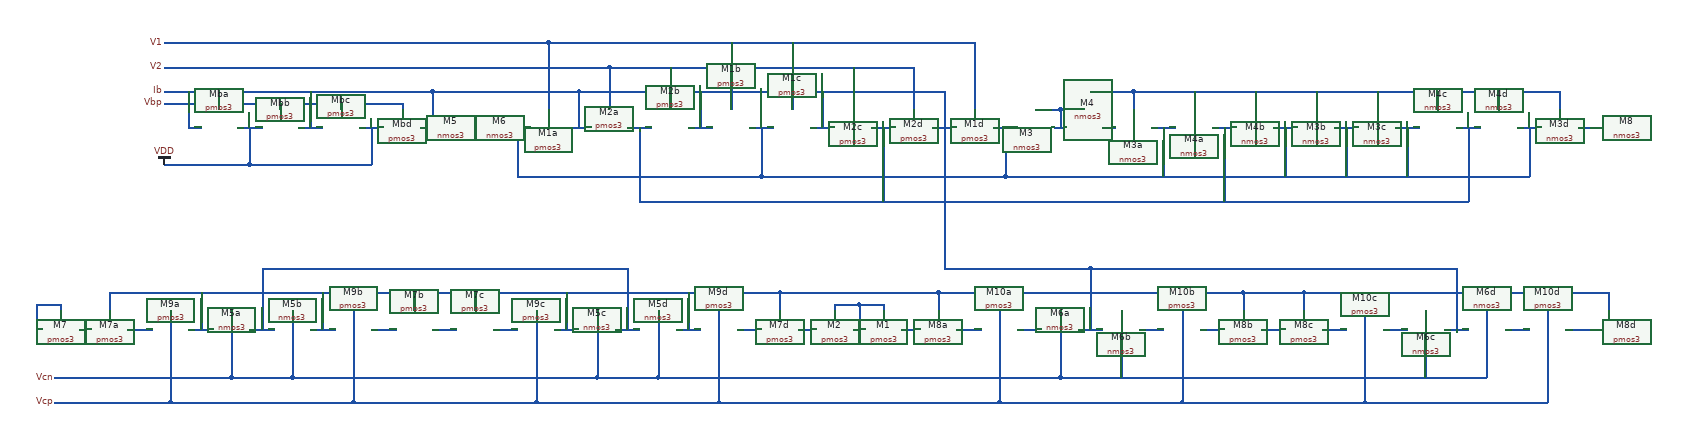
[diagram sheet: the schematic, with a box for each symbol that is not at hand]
v {xschem version=2.9.9 file_version=1.2 }
G {}
K {}
V {}
S {}
E {}
N 1240 -550 1280 -550 { lab=VDD}
N 1340 -550 1380 -550 { lab=Ib}
N 1440 -550 1480 -550 { lab=VDD}
N 1210 -590 1510 -590 { lab=Ib}
N 1510 -590 1510 -580 { lab=Ib}
N 1210 -590 1210 -580 { lab=Ib}
N 1160 -590 1210 -590 { lab=Ib}
N 1160 -550 1180 -550 { lab=Ib}
N 1780 -550 1820 -550 { lab=Ib}
N 1800 -610 1800 -550 { lab=Ib}
N 1800 -610 2400 -610 { lab=Ib}
N 2400 -610 2400 -550 { lab=Ib}
N 2380 -550 2420 -550 { lab=Ib}
N 1980 -550 2020 -550 { lab=Ib}
N 2000 -610 2000 -550 { lab=Ib}
N 2180 -550 2220 -550 { lab=Ib}
N 2200 -610 2200 -550 { lab=Ib}
N 1850 -650 1850 -580 { lab=V2}
N 1950 -650 1950 -580 { lab=V2}
N 2250 -650 2250 -580 { lab=V2}
N 2350 -650 2350 -580 { lab=V2}
N 1850 -650 2350 -650 { lab=V2}
N 1750 -690 1750 -580 { lab=V1}
N 1750 -690 2440 -690 { lab=V1}
N 2440 -690 2450 -690 { lab=V1}
N 2450 -690 2450 -580 { lab=V1}
N 2050 -690 2050 -580 { lab=V1}
N 2150 -690 2150 -580 { lab=V1}
N 1720 -650 1850 -650 { lab=V2}
N 1720 -690 1750 -690 { lab=V1}
N 2090 -550 2120 -550 { lab=#net1}
N 2080 -550 2090 -550 { lab=#net1}
N 2100 -550 2100 -470 { lab=#net1}
N 1700 -550 1700 -470 { lab=#net1}
N 1700 -470 2100 -470 { lab=#net1}
N 2100 -470 2500 -470 { lab=#net1}
N 2500 -550 2500 -470 { lab=#net1}
N 2480 -550 2500 -550 { lab=#net1}
N 1700 -550 1720 -550 { lab=#net1}
N 1700 -690 1720 -690 { lab=V1}
N 1700 -650 1720 -650 { lab=V2}
N 1880 -550 1920 -550 { lab=#net2}
N 1900 -550 1900 -450 { lab=#net2}
N 1900 -450 1900 -430 { lab=#net2}
N 1900 -430 2560 -430 { lab=#net2}
N 2500 -470 2560 -470 { lab=#net1}
N 2280 -550 2320 -550 { lab=#net2}
N 2300 -550 2300 -430 { lab=#net2}
N 2740 -550 2780 -550 { lab=#net1}
N 2840 -550 2880 -550 { lab=#net2}
N 2940 -550 2980 -550 { lab=#net1}
N 3040 -550 3080 -550 { lab=#net1}
N 3140 -550 3180 -550 { lab=#net1}
N 3240 -550 3280 -550 { lab=#net2}
N 3340 -550 3380 -550 { lab=#net1}
N 2710 -610 3410 -610 { lab=#net3}
N 3410 -610 3410 -580 { lab=#net3}
N 3310 -610 3310 -580 { lab=#net3}
N 3210 -610 3210 -580 { lab=#net3}
N 3110 -610 3110 -580 { lab=#net3}
N 3010 -610 3010 -580 { lab=#net3}
N 2910 -610 2910 -580 { lab=#net3}
N 2810 -610 2810 -580 { lab=#net3}
N 2710 -610 2710 -580 { lab=#net3}
N 2660 -610 2710 -610 { lab=#net3}
N 3440 -550 3460 -550 { lab=#net4}
N 2660 -550 2680 -550 { lab=#net5}
N 3060 -550 3060 -470 { lab=#net1}
N 2640 -610 2660 -610 { lab=#net3}
N 1030 -280 1030 -250 { lab=#net6}
N 1030 -280 1930 -280 { lab=#net6}
N 1930 -280 2130 -280 { lab=#net6}
N 2130 -280 2130 -250 { lab=#net6}
N 1530 -280 1530 -250 { lab=#net6}
N 1630 -280 1630 -250 { lab=#net6}
N 1380 -280 1380 -220 { lab=#net6}
N 1180 -280 1180 -220 { lab=#net6}
N 1780 -280 1780 -220 { lab=#net6}
N 1980 -280 1980 -220 { lab=#net6}
N 1160 -220 1200 -220 { lab=#net6}
N 1360 -220 1400 -220 { lab=#net6}
N 1460 -220 1500 -220 { lab=#net7}
N 1560 -220 1600 -220 { lab=#net8}
N 1660 -220 1700 -220 { lab=#net9}
N 1760 -220 1800 -220 { lab=#net6}
N 1860 -220 1900 -220 { lab=#net10}
N 1960 -220 2000 -220 { lab=#net6}
N 2060 -220 2100 -220 { lab=#net11}
N 1280 -320 1280 -220 { lab=#net10}
N 1280 -320 1880 -320 { lab=#net10}
N 1880 -320 1880 -220 { lab=#net10}
N 1260 -220 1300 -220 { lab=#net10}
N 1060 -220 1100 -220 { lab=#net12}
N 1330 -250 1330 -140 { lab=Vcn}
N 1230 -250 1230 -140 { lab=Vcn}
N 1830 -250 1830 -140 { lab=Vcn}
N 1930 -250 1930 -140 { lab=Vcn}
N 1830 -140 1930 -140 { lab=Vcn}
N 1330 -140 1830 -140 { lab=Vcn}
N 1230 -140 1330 -140 { lab=Vcn}
N 940 -140 1230 -140 { lab=Vcn}
N 1130 -250 1130 -100 { lab=Vcp}
N 1130 -100 1430 -100 { lab=Vcp}
N 1430 -250 1430 -100 { lab=Vcp}
N 1430 -100 1730 -100 { lab=Vcp}
N 1730 -250 1730 -100 { lab=Vcp}
N 1730 -100 2030 -100 { lab=Vcp}
N 2030 -250 2030 -100 { lab=Vcp}
N 940 -100 1130 -100 { lab=Vcp}
N 2420 -220 2460 -220 { lab=#net13}
N 2530 -220 2560 -220 { lab=#net14}
N 2520 -220 2530 -220 { lab=#net14}
N 2620 -220 2660 -220 { lab=Ib}
N 2720 -220 2760 -220 { lab=#net15}
N 2820 -220 2860 -220 { lab=#net16}
N 2920 -220 2960 -220 { lab=#net17}
N 3020 -220 3060 -220 { lab=#net18}
N 3120 -220 3160 -220 { lab=#net19}
N 3220 -220 3260 -220 { lab=Ib}
N 3320 -220 3360 -220 { lab=#net20}
N 3420 -220 3460 -220 { lab=#net21}
N 2640 -320 2640 -220 { lab=Ib}
N 2640 -320 3240 -320 { lab=Ib}
N 3240 -320 3240 -220 { lab=Ib}
N 1990 -140 2320 -140 { lab=Vcn}
N 2590 -250 2590 -140 { lab=Vcn}
N 2320 -140 2590 -140 { lab=Vcn}
N 2690 -250 2690 -140 { lab=Vcn}
N 3190 -250 3190 -140 { lab=Vcn}
N 3290 -250 3290 -140 { lab=Vcn}
N 2590 -140 3290 -140 { lab=Vcn}
N 2400 -320 2640 -320 { lab=Ib}
N 2400 -550 2400 -320 { lab=Ib}
N 2760 -550 2760 -470 { lab=#net1}
N 2960 -550 2960 -470 { lab=#net1}
N 3160 -550 3160 -470 { lab=#net1}
N 3360 -550 3360 -470 { lab=#net1}
N 2560 -470 2700 -470 { lab=#net1}
N 2860 -550 2860 -430 { lab=#net2}
N 3260 -550 3260 -430 { lab=#net2}
N 2090 -100 2490 -100 { lab=Vcp}
N 2490 -250 2490 -100 { lab=Vcp}
N 2790 -250 2790 -100 { lab=Vcp}
N 2490 -100 2790 -100 { lab=Vcp}
N 3090 -240 3090 -100 { lab=Vcp}
N 2790 -100 3090 -100 { lab=Vcp}
N 3390 -250 3390 -100 { lab=Vcp}
N 3090 -100 3390 -100 { lab=Vcp}
N 2260 -220 2270 -220 { lab=#net22}
N 2160 -220 2190 -220 { lab=#net23}
N 2330 -220 2360 -220 { lab=#net24}
N 2250 -220 2260 -220 { lab=#net22}
N 2220 -260 2220 -250 { lab=#net22}
N 2220 -260 2260 -260 { lab=#net22}
N 2260 -260 2260 -220 { lab=#net22}
N 2260 -260 2300 -260 { lab=#net22}
N 2300 -260 2300 -250 { lab=#net22}
N 1930 -140 1990 -140 { lab=Vcn}
N 2030 -100 2090 -100 { lab=Vcp}
N 2130 -280 2390 -280 { lab=#net6}
N 2390 -280 2390 -250 { lab=#net6}
N 2390 -280 2890 -280 { lab=#net6}
N 2890 -280 2890 -250 { lab=#net6}
N 2890 -280 2990 -280 { lab=#net6}
N 2990 -280 2990 -250 { lab=#net6}
N 2990 -280 3490 -280 { lab=#net6}
N 3490 -280 3490 -250 { lab=#net6}
N 1310 -590 1310 -580 { lab=Ib}
N 1410 -590 1410 -580 { lab=Ib}
N 1540 -550 1560 -550 { lab=Ib}
N 1560 -610 1560 -550 { lab=Ib}
N 1560 -610 1800 -610 { lab=Ib}
N 1260 -550 1260 -490 { lab=VDD}
N 1460 -550 1460 -490 { lab=VDD}
N 1260 -490 1460 -490 { lab=VDD}
N 1120 -490 1260 -490 { lab=VDD}
N 1120 -590 1160 -590 { lab=Vbp}
N 1160 -610 1160 -550 { lab=Ib}
N 1360 -610 1360 -550 { lab=Ib}
N 1120 -650 1700 -650 { lab=V2}
N 1120 -690 1700 -690 { lab=V1}
N 1120 -610 1560 -610 { lab=Ib}
N 980 -220 1000 -220 { lab=#net25}
N 910 -250 910 -220 { lab=#net26}
N 910 -260 910 -250 { lab=#net26}
N 910 -260 950 -260 { lab=#net26}
N 950 -260 950 -250 { lab=#net26}
N 910 -220 920 -220 { lab=#net26}
N 2700 -470 3350 -470 { lab=#net1}
N 3350 -470 3360 -470 { lab=#net1}
N 2560 -430 3260 -430 { lab=#net2}
N 2500 -550 2520 -550 { lab=#net1}
N 2580 -550 2600 -550 { lab=#net27}
N 2550 -580 2590 -580 { lab=#net27}
N 2590 -580 2590 -550 { lab=#net27}
N 2590 -580 2630 -580 { lab=#net27}
C {madvlsi/nmos3.sym} 2710 -550 1 0 {name=M3a
L=0.5
W=3
body=GND
nf=1
mult=1
ad="'int((nf+1)/2) * W/nf * 0.29'" 
pd="'2*int((nf+1)/2) * (W/nf + 0.29)'"
as="'int((nf+2)/2) * W/nf * 0.29'" 
ps="'2*int((nf+2)/2) * (W/nf + 0.29)'"
nrd="'0.29 / W'" nrs="'0.29 / W'"
sa=0 sb=0 sd=0
model=nfet_01v8
spiceprefix=X
}
C {madvlsi/nmos3.sym} 2810 -550 1 0 {name=M4a
L=0.5
W=3
body=GND
nf=1
mult=1
ad="'int((nf+1)/2) * W/nf * 0.29'" 
pd="'2*int((nf+1)/2) * (W/nf + 0.29)'"
as="'int((nf+2)/2) * W/nf * 0.29'" 
ps="'2*int((nf+2)/2) * (W/nf + 0.29)'"
nrd="'0.29 / W'" nrs="'0.29 / W'"
sa=0 sb=0 sd=0
model=nfet_01v8
spiceprefix=X
}
C {madvlsi/nmos3.sym} 2910 -550 1 0 {name=M4b
L=0.5
W=3
body=GND
nf=1
mult=1
ad="'int((nf+1)/2) * W/nf * 0.29'" 
pd="'2*int((nf+1)/2) * (W/nf + 0.29)'"
as="'int((nf+2)/2) * W/nf * 0.29'" 
ps="'2*int((nf+2)/2) * (W/nf + 0.29)'"
nrd="'0.29 / W'" nrs="'0.29 / W'"
sa=0 sb=0 sd=0
model=nfet_01v8
spiceprefix=X
}
C {madvlsi/nmos3.sym} 3010 -550 1 0 {name=M3b
L=0.5
W=3
body=GND
nf=1
mult=1
ad="'int((nf+1)/2) * W/nf * 0.29'" 
pd="'2*int((nf+1)/2) * (W/nf + 0.29)'"
as="'int((nf+2)/2) * W/nf * 0.29'" 
ps="'2*int((nf+2)/2) * (W/nf + 0.29)'"
nrd="'0.29 / W'" nrs="'0.29 / W'"
sa=0 sb=0 sd=0
model=nfet_01v8
spiceprefix=X
}
C {madvlsi/nmos3.sym} 3110 -550 1 0 {name=M3c
L=0.5
W=3
body=GND
nf=1
mult=1
ad="'int((nf+1)/2) * W/nf * 0.29'" 
pd="'2*int((nf+1)/2) * (W/nf + 0.29)'"
as="'int((nf+2)/2) * W/nf * 0.29'" 
ps="'2*int((nf+2)/2) * (W/nf + 0.29)'"
nrd="'0.29 / W'" nrs="'0.29 / W'"
sa=0 sb=0 sd=0
model=nfet_01v8
spiceprefix=X
}
C {madvlsi/nmos3.sym} 3210 -550 1 0 {name=M4c
L=0.5
W=3
body=GND
nf=1
mult=1
ad="'int((nf+1)/2) * W/nf * 0.29'" 
pd="'2*int((nf+1)/2) * (W/nf + 0.29)'"
as="'int((nf+2)/2) * W/nf * 0.29'" 
ps="'2*int((nf+2)/2) * (W/nf + 0.29)'"
nrd="'0.29 / W'" nrs="'0.29 / W'"
sa=0 sb=0 sd=0
model=nfet_01v8
spiceprefix=X
}
C {madvlsi/nmos3.sym} 3310 -550 1 0 {name=M4d
L=0.5
W=3
body=GND
nf=1
mult=1
ad="'int((nf+1)/2) * W/nf * 0.29'" 
pd="'2*int((nf+1)/2) * (W/nf + 0.29)'"
as="'int((nf+2)/2) * W/nf * 0.29'" 
ps="'2*int((nf+2)/2) * (W/nf + 0.29)'"
nrd="'0.29 / W'" nrs="'0.29 / W'"
sa=0 sb=0 sd=0
model=nfet_01v8
spiceprefix=X
}
C {madvlsi/nmos3.sym} 3410 -550 1 0 {name=M3d
L=0.5
W=3
body=GND
nf=1
mult=1
ad="'int((nf+1)/2) * W/nf * 0.29'" 
pd="'2*int((nf+1)/2) * (W/nf + 0.29)'"
as="'int((nf+2)/2) * W/nf * 0.29'" 
ps="'2*int((nf+2)/2) * (W/nf + 0.29)'"
nrd="'0.29 / W'" nrs="'0.29 / W'"
sa=0 sb=0 sd=0
model=nfet_01v8
spiceprefix=X
}
C {madvlsi/pmos3.sym} 1210 -550 1 0 {name=Mba
L=0.5
W=3
body=VDD
nf=1
mult=1
ad="'int((nf+1)/2) * W/nf * 0.29'" 
pd="'2*int((nf+1)/2) * (W/nf + 0.29)'"
as="'int((nf+2)/2) * W/nf * 0.29'" 
ps="'2*int((nf+2)/2) * (W/nf + 0.29)'"
nrd="'0.29 / W'" nrs="'0.29 / W'"
sa=0 sb=0 sd=0
model=pfet_01v8
spiceprefix=X
}
C {madvlsi/pmos3.sym} 1310 -550 1 0 {name=Mbb
L=0.5
W=3
body=VDD
nf=1
mult=1
ad="'int((nf+1)/2) * W/nf * 0.29'" 
pd="'2*int((nf+1)/2) * (W/nf + 0.29)'"
as="'int((nf+2)/2) * W/nf * 0.29'" 
ps="'2*int((nf+2)/2) * (W/nf + 0.29)'"
nrd="'0.29 / W'" nrs="'0.29 / W'"
sa=0 sb=0 sd=0
model=pfet_01v8
spiceprefix=X
}
C {madvlsi/pmos3.sym} 1410 -550 1 0 {name=Mbc
L=0.5
W=3
body=VDD
nf=1
mult=1
ad="'int((nf+1)/2) * W/nf * 0.29'" 
pd="'2*int((nf+1)/2) * (W/nf + 0.29)'"
as="'int((nf+2)/2) * W/nf * 0.29'" 
ps="'2*int((nf+2)/2) * (W/nf + 0.29)'"
nrd="'0.29 / W'" nrs="'0.29 / W'"
sa=0 sb=0 sd=0
model=pfet_01v8
spiceprefix=X
}
C {madvlsi/pmos3.sym} 1510 -550 1 0 {name=Mbd
L=0.5
W=3
body=VDD
nf=1
mult=1
ad="'int((nf+1)/2) * W/nf * 0.29'" 
pd="'2*int((nf+1)/2) * (W/nf + 0.29)'"
as="'int((nf+2)/2) * W/nf * 0.29'" 
ps="'2*int((nf+2)/2) * (W/nf + 0.29)'"
nrd="'0.29 / W'" nrs="'0.29 / W'"
sa=0 sb=0 sd=0
model=pfet_01v8
spiceprefix=X
}
C {madvlsi/pmos3.sym} 1750 -550 1 0 {name=M1a
L=0.5
W=3
body=VDD
nf=1
mult=1
ad="'int((nf+1)/2) * W/nf * 0.29'" 
pd="'2*int((nf+1)/2) * (W/nf + 0.29)'"
as="'int((nf+2)/2) * W/nf * 0.29'" 
ps="'2*int((nf+2)/2) * (W/nf + 0.29)'"
nrd="'0.29 / W'" nrs="'0.29 / W'"
sa=0 sb=0 sd=0
model=pfet_01v8
spiceprefix=X
}
C {madvlsi/pmos3.sym} 1850 -550 1 0 {name=M2a
L=0.5
W=3
body=VDD
nf=1
mult=1
ad="'int((nf+1)/2) * W/nf * 0.29'" 
pd="'2*int((nf+1)/2) * (W/nf + 0.29)'"
as="'int((nf+2)/2) * W/nf * 0.29'" 
ps="'2*int((nf+2)/2) * (W/nf + 0.29)'"
nrd="'0.29 / W'" nrs="'0.29 / W'"
sa=0 sb=0 sd=0
model=pfet_01v8
spiceprefix=X
}
C {madvlsi/pmos3.sym} 1950 -550 1 0 {name=M2b
L=0.5
W=3
body=VDD
nf=1
mult=1
ad="'int((nf+1)/2) * W/nf * 0.29'" 
pd="'2*int((nf+1)/2) * (W/nf + 0.29)'"
as="'int((nf+2)/2) * W/nf * 0.29'" 
ps="'2*int((nf+2)/2) * (W/nf + 0.29)'"
nrd="'0.29 / W'" nrs="'0.29 / W'"
sa=0 sb=0 sd=0
model=pfet_01v8
spiceprefix=X
}
C {madvlsi/pmos3.sym} 2050 -550 1 0 {name=M1b
L=0.5
W=3
body=VDD
nf=1
mult=1
ad="'int((nf+1)/2) * W/nf * 0.29'" 
pd="'2*int((nf+1)/2) * (W/nf + 0.29)'"
as="'int((nf+2)/2) * W/nf * 0.29'" 
ps="'2*int((nf+2)/2) * (W/nf + 0.29)'"
nrd="'0.29 / W'" nrs="'0.29 / W'"
sa=0 sb=0 sd=0
model=pfet_01v8
spiceprefix=X
}
C {madvlsi/pmos3.sym} 2150 -550 1 0 {name=M1c
L=0.5
W=3
body=VDD
nf=1
mult=1
ad="'int((nf+1)/2) * W/nf * 0.29'" 
pd="'2*int((nf+1)/2) * (W/nf + 0.29)'"
as="'int((nf+2)/2) * W/nf * 0.29'" 
ps="'2*int((nf+2)/2) * (W/nf + 0.29)'"
nrd="'0.29 / W'" nrs="'0.29 / W'"
sa=0 sb=0 sd=0
model=pfet_01v8
spiceprefix=X
}
C {madvlsi/pmos3.sym} 2250 -550 1 0 {name=M2c
L=0.5
W=3
body=VDD
nf=1
mult=1
ad="'int((nf+1)/2) * W/nf * 0.29'" 
pd="'2*int((nf+1)/2) * (W/nf + 0.29)'"
as="'int((nf+2)/2) * W/nf * 0.29'" 
ps="'2*int((nf+2)/2) * (W/nf + 0.29)'"
nrd="'0.29 / W'" nrs="'0.29 / W'"
sa=0 sb=0 sd=0
model=pfet_01v8
spiceprefix=X
}
C {madvlsi/pmos3.sym} 2350 -550 1 0 {name=M2d
L=0.5
W=3
body=VDD
nf=1
mult=1
ad="'int((nf+1)/2) * W/nf * 0.29'" 
pd="'2*int((nf+1)/2) * (W/nf + 0.29)'"
as="'int((nf+2)/2) * W/nf * 0.29'" 
ps="'2*int((nf+2)/2) * (W/nf + 0.29)'"
nrd="'0.29 / W'" nrs="'0.29 / W'"
sa=0 sb=0 sd=0
model=pfet_01v8
spiceprefix=X
}
C {madvlsi/pmos3.sym} 2450 -550 1 0 {name=M1d
L=0.5
W=3
body=VDD
nf=1
mult=1
ad="'int((nf+1)/2) * W/nf * 0.29'" 
pd="'2*int((nf+1)/2) * (W/nf + 0.29)'"
as="'int((nf+2)/2) * W/nf * 0.29'" 
ps="'2*int((nf+2)/2) * (W/nf + 0.29)'"
nrd="'0.29 / W'" nrs="'0.29 / W'"
sa=0 sb=0 sd=0
model=pfet_01v8
spiceprefix=X
}
C {madvlsi/pmos3.sym} 1030 -220 1 0 {name=M7a
L=0.5
W=3
body=VDD
nf=1
mult=1
ad="'int((nf+1)/2) * W/nf * 0.29'" 
pd="'2*int((nf+1)/2) * (W/nf + 0.29)'"
as="'int((nf+2)/2) * W/nf * 0.29'" 
ps="'2*int((nf+2)/2) * (W/nf + 0.29)'"
nrd="'0.29 / W'" nrs="'0.29 / W'"
sa=0 sb=0 sd=0
model=pfet_01v8
spiceprefix=X
}
C {madvlsi/pmos3.sym} 1130 -220 1 0 {name=M9a
L=0.5
W=3
body=VDD
nf=1
mult=1
ad="'int((nf+1)/2) * W/nf * 0.29'" 
pd="'2*int((nf+1)/2) * (W/nf + 0.29)'"
as="'int((nf+2)/2) * W/nf * 0.29'" 
ps="'2*int((nf+2)/2) * (W/nf + 0.29)'"
nrd="'0.29 / W'" nrs="'0.29 / W'"
sa=0 sb=0 sd=0
model=pfet_01v8
spiceprefix=X
}
C {madvlsi/nmos3.sym} 1230 -220 1 0 {name=M5a
L=0.5
W=3
body=GND
nf=1
mult=1
ad="'int((nf+1)/2) * W/nf * 0.29'" 
pd="'2*int((nf+1)/2) * (W/nf + 0.29)'"
as="'int((nf+2)/2) * W/nf * 0.29'" 
ps="'2*int((nf+2)/2) * (W/nf + 0.29)'"
nrd="'0.29 / W'" nrs="'0.29 / W'"
sa=0 sb=0 sd=0
model=nfet_01v8
spiceprefix=X
}
C {madvlsi/nmos3.sym} 1330 -220 1 0 {name=M5b
L=0.5
W=3
body=GND
nf=1
mult=1
ad="'int((nf+1)/2) * W/nf * 0.29'" 
pd="'2*int((nf+1)/2) * (W/nf + 0.29)'"
as="'int((nf+2)/2) * W/nf * 0.29'" 
ps="'2*int((nf+2)/2) * (W/nf + 0.29)'"
nrd="'0.29 / W'" nrs="'0.29 / W'"
sa=0 sb=0 sd=0
model=nfet_01v8
spiceprefix=X
}
C {madvlsi/pmos3.sym} 1430 -220 1 0 {name=M9b
L=0.5
W=3
body=VDD
nf=1
mult=1
ad="'int((nf+1)/2) * W/nf * 0.29'" 
pd="'2*int((nf+1)/2) * (W/nf + 0.29)'"
as="'int((nf+2)/2) * W/nf * 0.29'" 
ps="'2*int((nf+2)/2) * (W/nf + 0.29)'"
nrd="'0.29 / W'" nrs="'0.29 / W'"
sa=0 sb=0 sd=0
model=pfet_01v8
spiceprefix=X
}
C {madvlsi/pmos3.sym} 1530 -220 1 0 {name=M7b
L=0.5
W=3
body=VDD
nf=1
mult=1
ad="'int((nf+1)/2) * W/nf * 0.29'" 
pd="'2*int((nf+1)/2) * (W/nf + 0.29)'"
as="'int((nf+2)/2) * W/nf * 0.29'" 
ps="'2*int((nf+2)/2) * (W/nf + 0.29)'"
nrd="'0.29 / W'" nrs="'0.29 / W'"
sa=0 sb=0 sd=0
model=pfet_01v8
spiceprefix=X
}
C {madvlsi/pmos3.sym} 1630 -220 1 0 {name=M7c
L=0.5
W=3
body=VDD
nf=1
mult=1
ad="'int((nf+1)/2) * W/nf * 0.29'" 
pd="'2*int((nf+1)/2) * (W/nf + 0.29)'"
as="'int((nf+2)/2) * W/nf * 0.29'" 
ps="'2*int((nf+2)/2) * (W/nf + 0.29)'"
nrd="'0.29 / W'" nrs="'0.29 / W'"
sa=0 sb=0 sd=0
model=pfet_01v8
spiceprefix=X
}
C {madvlsi/pmos3.sym} 1730 -220 1 0 {name=M9c
L=0.5
W=3
body=VDD
nf=1
mult=1
ad="'int((nf+1)/2) * W/nf * 0.29'" 
pd="'2*int((nf+1)/2) * (W/nf + 0.29)'"
as="'int((nf+2)/2) * W/nf * 0.29'" 
ps="'2*int((nf+2)/2) * (W/nf + 0.29)'"
nrd="'0.29 / W'" nrs="'0.29 / W'"
sa=0 sb=0 sd=0
model=pfet_01v8
spiceprefix=X
}
C {madvlsi/nmos3.sym} 1830 -220 1 0 {name=M5c
L=0.5
W=3
body=GND
nf=1
mult=1
ad="'int((nf+1)/2) * W/nf * 0.29'" 
pd="'2*int((nf+1)/2) * (W/nf + 0.29)'"
as="'int((nf+2)/2) * W/nf * 0.29'" 
ps="'2*int((nf+2)/2) * (W/nf + 0.29)'"
nrd="'0.29 / W'" nrs="'0.29 / W'"
sa=0 sb=0 sd=0
model=nfet_01v8
spiceprefix=X
}
C {madvlsi/nmos3.sym} 1930 -220 1 0 {name=M5d
L=0.5
W=3
body=GND
nf=1
mult=1
ad="'int((nf+1)/2) * W/nf * 0.29'" 
pd="'2*int((nf+1)/2) * (W/nf + 0.29)'"
as="'int((nf+2)/2) * W/nf * 0.29'" 
ps="'2*int((nf+2)/2) * (W/nf + 0.29)'"
nrd="'0.29 / W'" nrs="'0.29 / W'"
sa=0 sb=0 sd=0
model=nfet_01v8
spiceprefix=X
}
C {madvlsi/pmos3.sym} 2030 -220 1 0 {name=M9d
L=0.5
W=3
body=VDD
nf=1
mult=1
ad="'int((nf+1)/2) * W/nf * 0.29'" 
pd="'2*int((nf+1)/2) * (W/nf + 0.29)'"
as="'int((nf+2)/2) * W/nf * 0.29'" 
ps="'2*int((nf+2)/2) * (W/nf + 0.29)'"
nrd="'0.29 / W'" nrs="'0.29 / W'"
sa=0 sb=0 sd=0
model=pfet_01v8
spiceprefix=X
}
C {madvlsi/pmos3.sym} 2130 -220 1 0 {name=M7d
L=0.5
W=3
body=VDD
nf=1
mult=1
ad="'int((nf+1)/2) * W/nf * 0.29'" 
pd="'2*int((nf+1)/2) * (W/nf + 0.29)'"
as="'int((nf+2)/2) * W/nf * 0.29'" 
ps="'2*int((nf+2)/2) * (W/nf + 0.29)'"
nrd="'0.29 / W'" nrs="'0.29 / W'"
sa=0 sb=0 sd=0
model=pfet_01v8
spiceprefix=X
}
C {madvlsi/pmos3.sym} 2390 -220 1 0 {name=M8a
L=0.5
W=3
body=VDD
nf=1
mult=1
ad="'int((nf+1)/2) * W/nf * 0.29'" 
pd="'2*int((nf+1)/2) * (W/nf + 0.29)'"
as="'int((nf+2)/2) * W/nf * 0.29'" 
ps="'2*int((nf+2)/2) * (W/nf + 0.29)'"
nrd="'0.29 / W'" nrs="'0.29 / W'"
sa=0 sb=0 sd=0
model=pfet_01v8
spiceprefix=X
}
C {madvlsi/pmos3.sym} 2490 -220 1 0 {name=M10a
L=0.5
W=3
body=VDD
nf=1
mult=1
ad="'int((nf+1)/2) * W/nf * 0.29'" 
pd="'2*int((nf+1)/2) * (W/nf + 0.29)'"
as="'int((nf+2)/2) * W/nf * 0.29'" 
ps="'2*int((nf+2)/2) * (W/nf + 0.29)'"
nrd="'0.29 / W'" nrs="'0.29 / W'"
sa=0 sb=0 sd=0
model=pfet_01v8
spiceprefix=X
}
C {madvlsi/nmos3.sym} 2590 -220 1 0 {name=M6a
L=0.5
W=3
body=GND
nf=1
mult=1
ad="'int((nf+1)/2) * W/nf * 0.29'" 
pd="'2*int((nf+1)/2) * (W/nf + 0.29)'"
as="'int((nf+2)/2) * W/nf * 0.29'" 
ps="'2*int((nf+2)/2) * (W/nf + 0.29)'"
nrd="'0.29 / W'" nrs="'0.29 / W'"
sa=0 sb=0 sd=0
model=nfet_01v8
spiceprefix=X
}
C {madvlsi/nmos3.sym} 2690 -220 1 0 {name=M6b
L=0.5
W=3
body=GND
nf=1
mult=1
ad="'int((nf+1)/2) * W/nf * 0.29'" 
pd="'2*int((nf+1)/2) * (W/nf + 0.29)'"
as="'int((nf+2)/2) * W/nf * 0.29'" 
ps="'2*int((nf+2)/2) * (W/nf + 0.29)'"
nrd="'0.29 / W'" nrs="'0.29 / W'"
sa=0 sb=0 sd=0
model=nfet_01v8
spiceprefix=X
}
C {madvlsi/pmos3.sym} 2790 -220 1 0 {name=M10b
L=0.5
W=3
body=VDD
nf=1
mult=1
ad="'int((nf+1)/2) * W/nf * 0.29'" 
pd="'2*int((nf+1)/2) * (W/nf + 0.29)'"
as="'int((nf+2)/2) * W/nf * 0.29'" 
ps="'2*int((nf+2)/2) * (W/nf + 0.29)'"
nrd="'0.29 / W'" nrs="'0.29 / W'"
sa=0 sb=0 sd=0
model=pfet_01v8
spiceprefix=X
}
C {madvlsi/pmos3.sym} 2890 -220 1 0 {name=M8b
L=0.5
W=3
body=VDD
nf=1
mult=1
ad="'int((nf+1)/2) * W/nf * 0.29'" 
pd="'2*int((nf+1)/2) * (W/nf + 0.29)'"
as="'int((nf+2)/2) * W/nf * 0.29'" 
ps="'2*int((nf+2)/2) * (W/nf + 0.29)'"
nrd="'0.29 / W'" nrs="'0.29 / W'"
sa=0 sb=0 sd=0
model=pfet_01v8
spiceprefix=X
}
C {madvlsi/pmos3.sym} 2990 -220 1 0 {name=M8c
L=0.5
W=3
body=VDD
nf=1
mult=1
ad="'int((nf+1)/2) * W/nf * 0.29'" 
pd="'2*int((nf+1)/2) * (W/nf + 0.29)'"
as="'int((nf+2)/2) * W/nf * 0.29'" 
ps="'2*int((nf+2)/2) * (W/nf + 0.29)'"
nrd="'0.29 / W'" nrs="'0.29 / W'"
sa=0 sb=0 sd=0
model=pfet_01v8
spiceprefix=X
}
C {madvlsi/pmos3.sym} 3090 -220 1 0 {name=M10c
L=0.5
W=3
body=VDD
nf=1
mult=1
ad="'int((nf+1)/2) * W/nf * 0.29'" 
pd="'2*int((nf+1)/2) * (W/nf + 0.29)'"
as="'int((nf+2)/2) * W/nf * 0.29'" 
ps="'2*int((nf+2)/2) * (W/nf + 0.29)'"
nrd="'0.29 / W'" nrs="'0.29 / W'"
sa=0 sb=0 sd=0
model=pfet_01v8
spiceprefix=X
}
C {madvlsi/nmos3.sym} 3190 -220 1 0 {name=M6c
L=0.5
W=3
body=GND
nf=1
mult=1
ad="'int((nf+1)/2) * W/nf * 0.29'" 
pd="'2*int((nf+1)/2) * (W/nf + 0.29)'"
as="'int((nf+2)/2) * W/nf * 0.29'" 
ps="'2*int((nf+2)/2) * (W/nf + 0.29)'"
nrd="'0.29 / W'" nrs="'0.29 / W'"
sa=0 sb=0 sd=0
model=nfet_01v8
spiceprefix=X
}
C {madvlsi/nmos3.sym} 3290 -220 1 0 {name=M6d
L=0.5
W=3
body=GND
nf=1
mult=1
ad="'int((nf+1)/2) * W/nf * 0.29'" 
pd="'2*int((nf+1)/2) * (W/nf + 0.29)'"
as="'int((nf+2)/2) * W/nf * 0.29'" 
ps="'2*int((nf+2)/2) * (W/nf + 0.29)'"
nrd="'0.29 / W'" nrs="'0.29 / W'"
sa=0 sb=0 sd=0
model=nfet_01v8
spiceprefix=X
}
C {madvlsi/pmos3.sym} 3390 -220 1 0 {name=M10d
L=0.5
W=3
body=VDD
nf=1
mult=1
ad="'int((nf+1)/2) * W/nf * 0.29'" 
pd="'2*int((nf+1)/2) * (W/nf + 0.29)'"
as="'int((nf+2)/2) * W/nf * 0.29'" 
ps="'2*int((nf+2)/2) * (W/nf + 0.29)'"
nrd="'0.29 / W'" nrs="'0.29 / W'"
sa=0 sb=0 sd=0
model=pfet_01v8
spiceprefix=X
}
C {madvlsi/pmos3.sym} 3490 -220 1 0 {name=M8d
L=0.5
W=3
body=VDD
nf=1
mult=1
ad="'int((nf+1)/2) * W/nf * 0.29'" 
pd="'2*int((nf+1)/2) * (W/nf + 0.29)'"
as="'int((nf+2)/2) * W/nf * 0.29'" 
ps="'2*int((nf+2)/2) * (W/nf + 0.29)'"
nrd="'0.29 / W'" nrs="'0.29 / W'"
sa=0 sb=0 sd=0
model=pfet_01v8
spiceprefix=X
}
C {madvlsi/pmos3.sym} 2300 -220 1 0 {name=M1
L=0.5
W=3
body=VDD
nf=1
mult=1
ad="'int((nf+1)/2) * W/nf * 0.29'" 
pd="'2*int((nf+1)/2) * (W/nf + 0.29)'"
as="'int((nf+2)/2) * W/nf * 0.29'" 
ps="'2*int((nf+2)/2) * (W/nf + 0.29)'"
nrd="'0.29 / W'" nrs="'0.29 / W'"
sa=0 sb=0 sd=0
model=pfet_01v8
spiceprefix=X
}
C {madvlsi/pmos3.sym} 2220 -220 1 0 {name=M2
L=0.5
W=3
body=VDD
nf=1
mult=1
ad="'int((nf+1)/2) * W/nf * 0.29'" 
pd="'2*int((nf+1)/2) * (W/nf + 0.29)'"
as="'int((nf+2)/2) * W/nf * 0.29'" 
ps="'2*int((nf+2)/2) * (W/nf + 0.29)'"
nrd="'0.29 / W'" nrs="'0.29 / W'"
sa=0 sb=0 sd=0
model=pfet_01v8
spiceprefix=X
}
C {devices/lab_pin.sym} 1120 -610 0 0 {name=l1 sig_type=std_logic lab=Ib}
C {devices/lab_pin.sym} 1120 -590 0 0 {name=l2 sig_type=std_logic lab=Vbp}
C {devices/lab_pin.sym} 1120 -650 0 0 {name=l3 sig_type=std_logic lab=V2}
C {devices/lab_pin.sym} 1120 -690 0 0 {name=l4 sig_type=std_logic lab=V1}
C {madvlsi/vdd.sym} 1120 -490 0 0 {name=l5 lab=VDD}
C {madvlsi/nmos3.sym} 2550 -550 1 0 {name=M3
L=0.5
W=3
body=GND
nf=1
mult=1
ad="'int((nf+1)/2) * W/nf * 0.29'" 
pd="'2*int((nf+1)/2) * (W/nf + 0.29)'"
as="'int((nf+2)/2) * W/nf * 0.29'" 
ps="'2*int((nf+2)/2) * (W/nf + 0.29)'"
nrd="'0.29 / W'" nrs="'0.29 / W'"
sa=0 sb=0 sd=0
model=nfet_01v8
spiceprefix=X
}
C {madvlsi/nmos3.sym} 2630 -550 1 0 {name=M4
L=0.5
W=3
body=GND
nf=1
mult=1
ad="'int((nf+1)/2) * W/nf * 0.29'" 
pd="'2*int((nf+1)/2) * (W/nf + 0.29)'"
as="'int((nf+2)/2) * W/nf * 0.29'" 
ps="'2*int((nf+2)/2) * (W/nf + 0.29)'"
nrd="'0.29 / W'" nrs="'0.29 / W'"
sa=0 sb=0 sd=0
model=nfet_01v8
spiceprefix=X
}
C {madvlsi/nmos3.sym} 1590 -550 1 0 {name=M5
L=0.5
W=3
body=GND
nf=1
mult=1
ad="'int((nf+1)/2) * W/nf * 0.29'" 
pd="'2*int((nf+1)/2) * (W/nf + 0.29)'"
as="'int((nf+2)/2) * W/nf * 0.29'" 
ps="'2*int((nf+2)/2) * (W/nf + 0.29)'"
nrd="'0.29 / W'" nrs="'0.29 / W'"
sa=0 sb=0 sd=0
model=nfet_01v8
spiceprefix=X
}
C {madvlsi/nmos3.sym} 1670 -550 1 0 {name=M6
L=0.5
W=3
body=GND
nf=1
mult=1
ad="'int((nf+1)/2) * W/nf * 0.29'" 
pd="'2*int((nf+1)/2) * (W/nf + 0.29)'"
as="'int((nf+2)/2) * W/nf * 0.29'" 
ps="'2*int((nf+2)/2) * (W/nf + 0.29)'"
nrd="'0.29 / W'" nrs="'0.29 / W'"
sa=0 sb=0 sd=0
model=nfet_01v8
spiceprefix=X
}
C {devices/lab_pin.sym} 940 -100 0 0 {name=l6 sig_type=std_logic lab=Vcp}
C {devices/lab_pin.sym} 940 -140 0 0 {name=l7 sig_type=std_logic lab=Vcn}
C {madvlsi/pmos3.sym} 950 -220 1 0 {name=M7
L=0.5
W=3
body=VDD
nf=1
mult=1
ad="'int((nf+1)/2) * W/nf * 0.29'" 
pd="'2*int((nf+1)/2) * (W/nf + 0.29)'"
as="'int((nf+2)/2) * W/nf * 0.29'" 
ps="'2*int((nf+2)/2) * (W/nf + 0.29)'"
nrd="'0.29 / W'" nrs="'0.29 / W'"
sa=0 sb=0 sd=0
model=pfet_01v8
spiceprefix=X
}
C {madvlsi/nmos3.sym} 3490 -550 1 0 {name=M8
L=0.5
W=3
body=GND
nf=1
mult=1
ad="'int((nf+1)/2) * W/nf * 0.29'" 
pd="'2*int((nf+1)/2) * (W/nf + 0.29)'"
as="'int((nf+2)/2) * W/nf * 0.29'" 
ps="'2*int((nf+2)/2) * (W/nf + 0.29)'"
nrd="'0.29 / W'" nrs="'0.29 / W'"
sa=0 sb=0 sd=0
model=nfet_01v8
spiceprefix=X
}
